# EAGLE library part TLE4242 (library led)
Adjustable LED Driver Source: Infineon .. tle4242.pdf

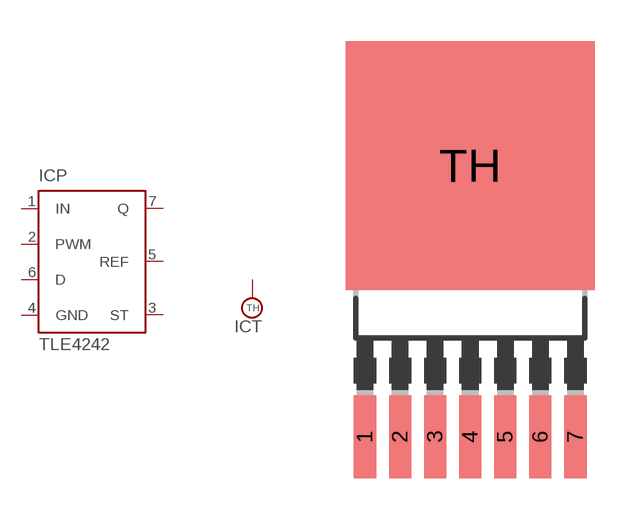
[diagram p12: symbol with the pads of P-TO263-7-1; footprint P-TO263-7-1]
Designator prefix IC; gates P=TLE4242 T=THERMAL

## TLE4242  [P-TO263-7-1]
1  P:IN  in
2  P:PWM  in
3  P:ST  oc
4  P:GND  pwr
5  P:REF  in
6  P:D  pas
7  P:Q  out
TH  T:TH  pas

## Footprint P-TO263-7-1 (pad centres in mm)
P-TO263-7-1 (Plastic Transistor Single Outline) Source: Infineon .. tle4242.pdf
smd 0.8 x 3: 1 -3.81,-3.475; 2 -2.54,-3.475; 3 -1.27,-3.475; 4 0,-3.475; 5 1.27,-3.475; 6 2.54,-3.475; 7 3.81,-3.475
smd 9 x 9: TH 0,6.35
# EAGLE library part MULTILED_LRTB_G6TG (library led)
6-lead MULTILED® Enhanced optical Power LED (ThinFilm® / ThinGaN®) Source. OSRAM - LRTB_G6TG.pdf

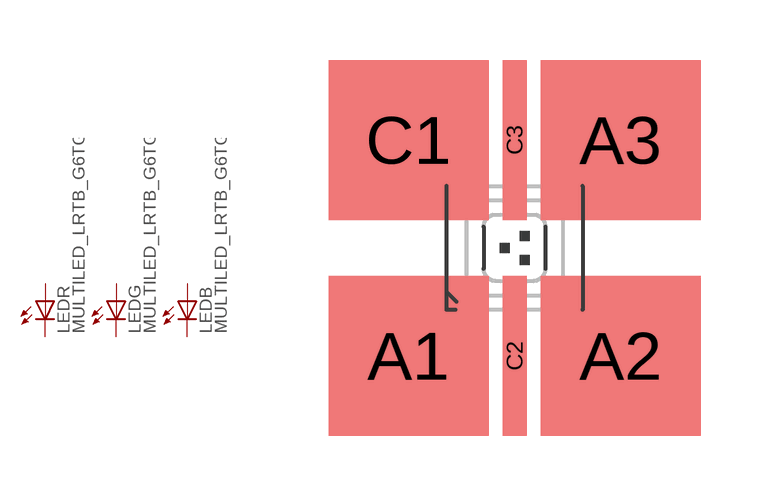
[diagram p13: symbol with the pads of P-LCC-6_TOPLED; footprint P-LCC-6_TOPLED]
Designator prefix LED; gates R=LED G=LED B=LED

## MULTILED_LRTB_G6TG  [P-LCC-6_TOPLED]
A1  R:A  pas
A2  G:A  pas
A3  B:A  pas
C1  R:C  pas
C2  G:C  pas
C3  B:C  pas

## Footprint P-LCC-6_TOPLED (pad centres in mm)
P-LCC-6 TOPLED MULTILED® Source: OSRAM - LRTB_G6TG.pdf
smd 4 x 4: A1 -2.65,-2.7; A2 2.65,-2.7; A3 2.65,2.7; C1 -2.65,2.7
smd 0.6 x 4: C2 0,-2.7; C3 0,2.7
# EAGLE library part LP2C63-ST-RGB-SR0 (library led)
1.5W RGB HIGH POWER LED Source: http://www.ledtech.com.tw .. LP2C63-ST-RGB-SR0.SPEC.pdf

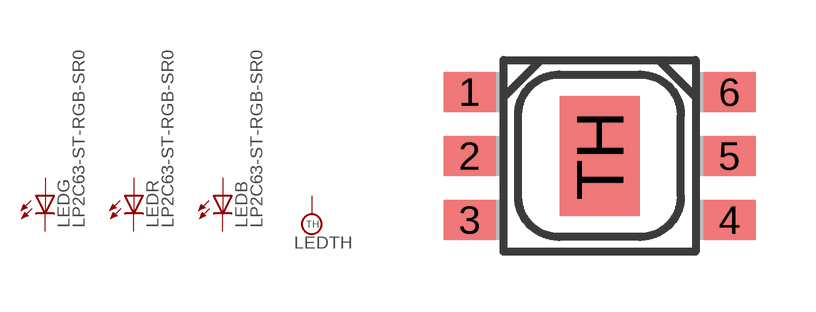
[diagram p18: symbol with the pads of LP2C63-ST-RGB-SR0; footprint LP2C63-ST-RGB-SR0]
Designator prefix LED; gates G=LED R=LED B=LED TH=THERMAL

## LP2C63-ST-RGB-SR0  [LP2C63-ST-RGB-SR0]
1  G:A  pas
2  R:A  pas
3  B:A  pas
4  B:C  pas
5  R:C  pas
6  G:C  pas
TH  TH:TH  pas

## Footprint LP2C63-ST-RGB-SR0 (pad centres in mm)
1.5W RGB HIGH POWER LED LEDTECH ELECTRONICS CORP. Source: LP2C63-ST-RGB-SR0.SPEC.pdf
smd 1.3 x 1: 1 -3.25,1.6; 2 -3.25,0; 3 -3.25,-1.6; 4 3.25,-1.6; 5 3.25,0; 6 3.25,1.6
smd 2 x 3: TH 0,0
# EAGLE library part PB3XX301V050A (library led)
Self-addressed led , single point control with integrated RGB leds and drive IC Easy control by MCU. Source: DycolED.pdf Data sheet

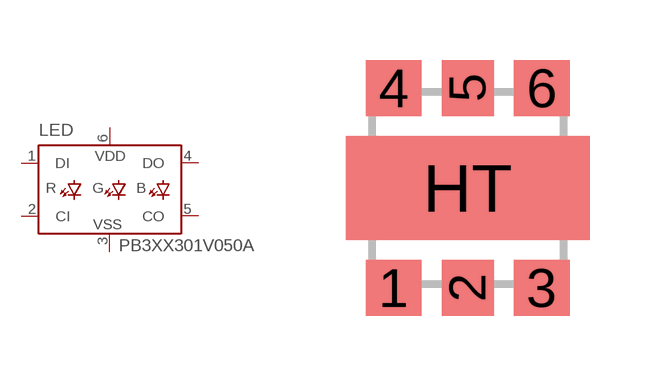
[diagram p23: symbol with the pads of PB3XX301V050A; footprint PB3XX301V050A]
Designator prefix LED

## PB3XX301V050A  [PB3XX301V050A]
1  DI  in
2  CI  in
3  VSS  pwr
4  DO  out
5  CO  out
6  VDD  pwr

## Footprint PB3XX301V050A (pad centres in mm)
RGB LED with integrated controller chip Source: Data sheedt DycoLED.pdf http://www.ubleds.com.tw
smd 1.4 x 1.4: 1 -1.85,-2.5; 3 1.85,-2.5; 4 -1.85,2.5; 6 1.85,2.5
smd 1.3 x 1.4: 2 0,-2.5; 5 0,2.5
smd 6.1 x 2.6: HT 0,0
